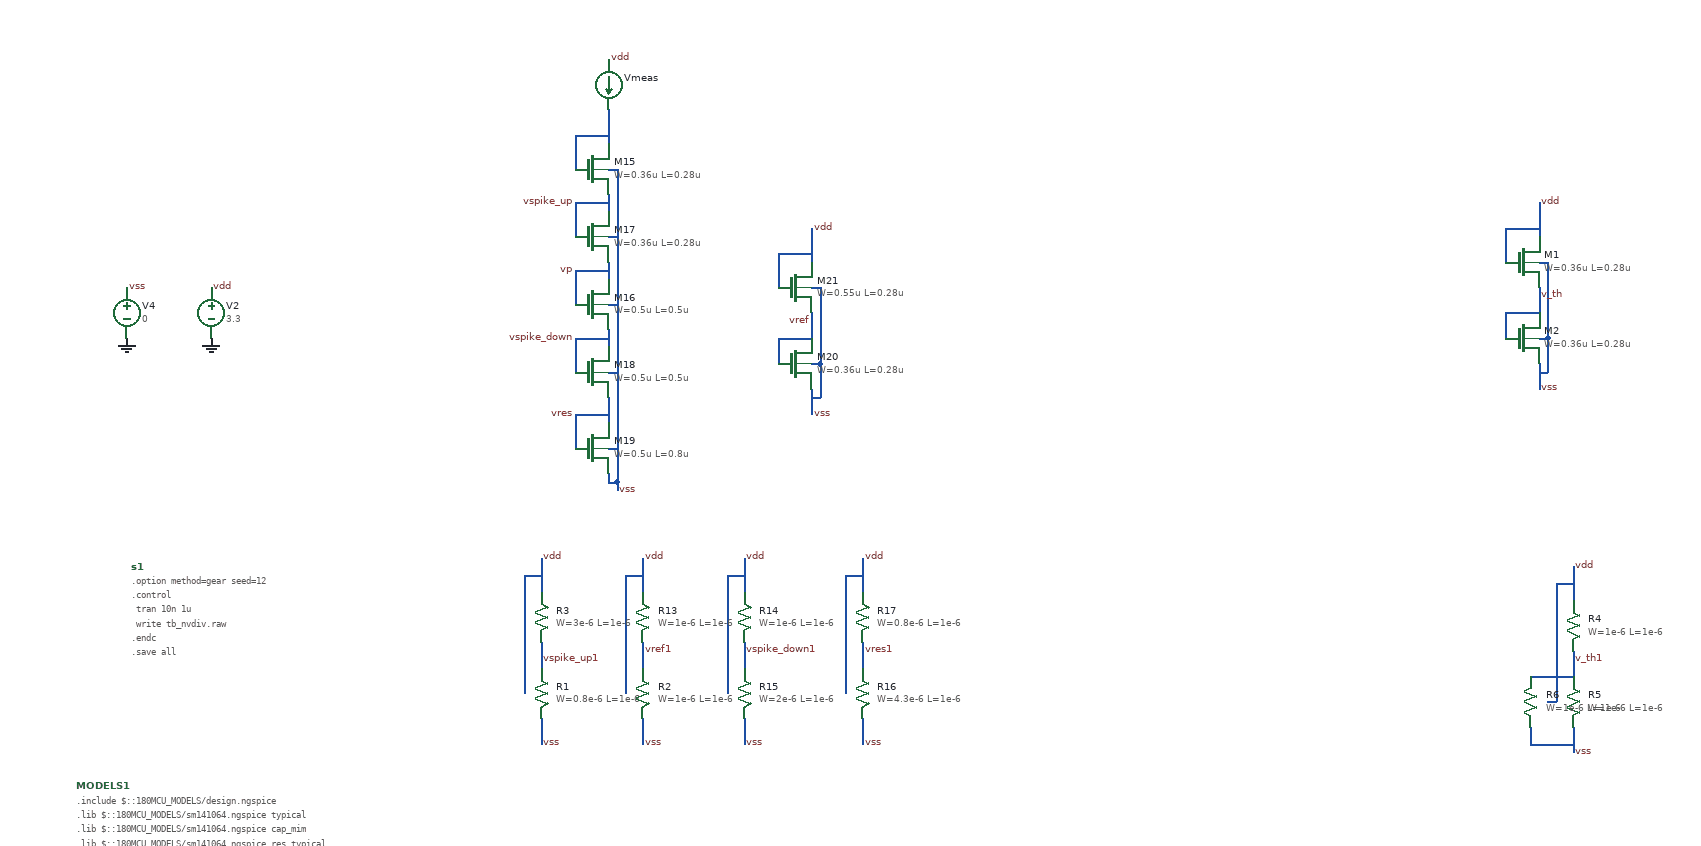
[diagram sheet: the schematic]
v {xschem version=3.4.7 file_version=1.2}
G {}
K {}
V {}
S {}
E {}
B 2 1110 -970 1580 -570 {flags=graph
y1=0
y2=3.3
ypos1=0
ypos2=2
divy=5
subdivy=1
unity=1
x1=0
x2=1e-06
divx=5
subdivx=1
xlabmag=1.0
ylabmag=1.0
dataset=-1
unitx=1
logx=0
logy=0
color="4 10 6 7"
node="vspike_up
vref
vspike_down
vres"}
B 2 1110 -570 1580 -170 {flags=graph
y1=0
y2=3.4
ypos1=0
ypos2=2
divy=5
subdivy=1
unity=1
x1=0
x2=1e-06
divx=5
subdivx=1
xlabmag=1.0
ylabmag=1.0
dataset=-1
unitx=1
logx=0
logy=0
color="4 10 6 7"
node="vspike_up1
vref1
vspike_down1
vres1"}
B 2 1910 -970 2380 -570 {flags=graph
y2=3.3
ypos1=0
ypos2=2
divy=5
subdivy=1
unity=1
x1=0
x2=1e-06
divx=5
subdivx=1
xlabmag=1.0
ylabmag=1.0
dataset=-1
unitx=1
logx=0
logy=0
color=4
node=v_th
y1=0}
B 2 1910 -570 2380 -170 {flags=graph
y1=0
y2=3.4
ypos1=0
ypos2=2
divy=5
subdivy=1
unity=1
x1=0
x2=1e-06
divx=5
subdivx=1
xlabmag=1.0
ylabmag=1.0
dataset=-1
unitx=1
logx=0
logy=0
color=4
node=v_th1}
N 630 -1000 630 -960 {lab=vdd}
N 590 -970 590 -930 {lab=vdd}
N 590 -970 630 -970 {lab=vdd}
N 630 -930 640 -930 {lab=vss}
N 640 -930 640 -640 {lab=vss}
N 630 -850 640 -850 {lab=vss}
N 630 -770 640 -770 {lab=vss}
N 630 -690 640 -690 {lab=vss}
N 630 -740 630 -720 {lab=vspike_down}
N 630 -820 630 -800 {lab=vp}
N 630 -900 630 -880 {lab=vspike_up}
N 590 -890 590 -850 {lab=vspike_up}
N 590 -890 630 -890 {lab=vspike_up}
N 590 -810 590 -770 {lab=vp}
N 590 -810 630 -810 {lab=vp}
N 590 -730 590 -690 {lab=vspike_down}
N 590 -730 630 -730 {lab=vspike_down}
N 630 -660 630 -650 {lab=vres}
N 630 -600 640 -600 {lab=vss}
N 630 -650 630 -630 {lab=vres}
N 590 -640 590 -600 {lab=vres}
N 590 -640 630 -640 {lab=vres}
N 630 -570 630 -560 {lab=vss}
N 640 -640 640 -560 {lab=vss}
N 640 -560 640 -550 {lab=vss}
N 630 -560 640 -560 {lab=vss}
N 870 -860 870 -820 {lab=vdd}
N 870 -760 870 -730 {lab=vref}
N 870 -670 870 -640 {lab=vss}
N 830 -830 830 -790 {lab=vdd}
N 830 -830 870 -830 {lab=vdd}
N 830 -730 830 -700 {lab=vref}
N 830 -730 870 -730 {lab=vref}
N 870 -790 880 -790 {lab=vss}
N 880 -790 880 -700 {lab=vss}
N 870 -700 880 -700 {lab=vss}
N 880 -700 880 -660 {lab=vss}
N 870 -660 880 -660 {lab=vss}
N 550 -470 550 -430 {lab=vdd}
N 530 -400 530 -310 {lab=vdd}
N 530 -450 530 -400 {lab=vdd}
N 530 -450 550 -450 {lab=vdd}
N 550 -370 550 -340 {lab=vspike_up1}
N 550 -280 550 -250 {lab=vss}
N 670 -470 670 -430 {lab=vdd}
N 650 -400 650 -310 {lab=vdd}
N 650 -450 650 -400 {lab=vdd}
N 650 -450 670 -450 {lab=vdd}
N 670 -370 670 -340 {lab=vref1}
N 670 -280 670 -250 {lab=vss}
N 790 -470 790 -430 {lab=vdd}
N 770 -400 770 -310 {lab=vdd}
N 770 -450 770 -400 {lab=vdd}
N 770 -450 790 -450 {lab=vdd}
N 790 -370 790 -340 {lab=vspike_down1}
N 790 -280 790 -250 {lab=vss}
N 930 -470 930 -430 {lab=vdd}
N 910 -400 910 -310 {lab=vdd}
N 910 -450 910 -400 {lab=vdd}
N 910 -450 930 -450 {lab=vdd}
N 930 -370 930 -340 {lab=vres1}
N 930 -280 930 -250 {lab=vss}
N 1770 -460 1770 -420 {lab=vdd}
N 1750 -390 1750 -300 {lab=vdd}
N 1750 -440 1750 -390 {lab=vdd}
N 1750 -440 1770 -440 {lab=vdd}
N 1770 -360 1770 -330 {lab=v_th1}
N 1770 -270 1770 -240 {lab=vss}
N 1720 -330 1770 -330 {lab=v_th1}
N 1720 -270 1720 -250 {lab=vss}
N 1740 -300 1750 -300 {lab=vdd}
N 1720 -250 1770 -250 {lab=vss}
N 1730 -890 1730 -850 {lab=vdd}
N 1730 -790 1730 -760 {lab=v_th}
N 1730 -700 1730 -670 {lab=vss}
N 1690 -860 1690 -820 {lab=vdd}
N 1690 -860 1730 -860 {lab=vdd}
N 1690 -760 1690 -730 {lab=v_th}
N 1690 -760 1730 -760 {lab=v_th}
N 1730 -820 1740 -820 {lab=vss}
N 1740 -820 1740 -730 {lab=vss}
N 1730 -730 1740 -730 {lab=vss}
N 1740 -730 1740 -690 {lab=vss}
N 1730 -690 1740 -690 {lab=vss}
C {title.sym} 160 0 0 0 {name=l1 author="Oscar Islas"}
C {vsource.sym} 160 -760 0 1 {name=V2 value=3.3 savecurrent=false}
C {gnd.sym} 160 -730 0 0 {name=l6 lab=GND}
C {lab_pin.sym} 160 -790 0 1 {name=p87 sig_type=std_logic lab=vdd}
C {devices/code_shown.sym} 65 -460 0 0 {name=s1 only_toplevel=false value="
.option method=gear seed=12
.control
    tran 10n 1u
    write tb_nvdiv.raw
.endc
.save all
"
spice_ignore=False}
C {devices/code_shown.sym} 0 -200 0 0 {name=MODELS1 only_toplevel=true
format="tcleval( @value )"
value="
.include $::180MCU_MODELS/design.ngspice
.lib $::180MCU_MODELS/sm141064.ngspice typical
.lib $::180MCU_MODELS/sm141064.ngspice cap_mim
.lib $::180MCU_MODELS/sm141064.ngspice res_typical
.lib $::180MCU_MODELS/sm141064.ngspice moscap_typical
.lib $::180MCU_MODELS/sm141064.ngspice mimcap_typical
"}
C {gnd.sym} 60 -730 0 0 {name=l3 lab=GND}
C {lab_pin.sym} 60 -790 0 1 {name=p1 sig_type=std_logic lab=vss}
C {vsource.sym} 60 -760 0 1 {name=V4 value=0 savecurrent=false}
C {launcher.sym} 860 -930 0 0 {name=h1
descr="load waves" 
tclcommand="xschem raw_read $netlist_dir/tb_nvdiv.raw tran"
}
C {lab_pin.sym} 630 -1060 0 1 {name=p9 sig_type=std_logic lab=vdd}
C {symbols/nfet_03v3.sym} 610 -930 0 0 {name=M15
L=0.28u
W=0.36u
nf=1
m=1
ad="'int((nf+1)/2) * W/nf * 0.18u'"
pd="'2*int((nf+1)/2) * (W/nf + 0.18u)'"
as="'int((nf+2)/2) * W/nf * 0.18u'"
ps="'2*int((nf+2)/2) * (W/nf + 0.18u)'"
nrd="'0.18u / W'" nrs="'0.18u / W'"
sa=0 sb=0 sd=0
model=nfet_03v3
spiceprefix=X
}
C {symbols/nfet_03v3.sym} 610 -690 0 0 {name=M18
L=0.5u
W=0.5u
nf=1
m=1
ad="'int((nf+1)/2) * W/nf * 0.18u'"
pd="'2*int((nf+1)/2) * (W/nf + 0.18u)'"
as="'int((nf+2)/2) * W/nf * 0.18u'"
ps="'2*int((nf+2)/2) * (W/nf + 0.18u)'"
nrd="'0.18u / W'" nrs="'0.18u / W'"
sa=0 sb=0 sd=0
model=nfet_03v3
spiceprefix=X
}
C {lab_pin.sym} 590 -890 0 0 {name=p11 sig_type=std_logic lab=vspike_up}
C {lab_pin.sym} 590 -810 0 0 {name=p12 sig_type=std_logic lab=vp}
C {lab_pin.sym} 590 -730 0 0 {name=p13 sig_type=std_logic lab=vspike_down}
C {lab_pin.sym} 640 -550 0 1 {name=p14 sig_type=std_logic lab=vss}
C {lab_pin.sym} 590 -640 0 0 {name=p15 sig_type=std_logic lab=vres}
C {lab_pin.sym} 870 -750 0 0 {name=p10 sig_type=std_logic lab=vref}
C {symbols/nfet_03v3.sym} 610 -770 0 0 {name=M16
L=0.5u
W=0.5u
nf=1
m=1
ad="'int((nf+1)/2) * W/nf * 0.18u'"
pd="'2*int((nf+1)/2) * (W/nf + 0.18u)'"
as="'int((nf+2)/2) * W/nf * 0.18u'"
ps="'2*int((nf+2)/2) * (W/nf + 0.18u)'"
nrd="'0.18u / W'" nrs="'0.18u / W'"
sa=0 sb=0 sd=0
model=nfet_03v3
spiceprefix=X
}
C {symbols/nfet_03v3.sym} 610 -600 0 0 {name=M19
L=0.8u
W=0.5u
nf=1
m=1
ad="'int((nf+1)/2) * W/nf * 0.18u'"
pd="'2*int((nf+1)/2) * (W/nf + 0.18u)'"
as="'int((nf+2)/2) * W/nf * 0.18u'"
ps="'2*int((nf+2)/2) * (W/nf + 0.18u)'"
nrd="'0.18u / W'" nrs="'0.18u / W'"
sa=0 sb=0 sd=0
model=nfet_03v3
spiceprefix=X
}
C {symbols/nfet_03v3.sym} 610 -850 0 0 {name=M17
L=0.28u
W=0.36u
nf=1
m=1
ad="'int((nf+1)/2) * W/nf * 0.18u'"
pd="'2*int((nf+1)/2) * (W/nf + 0.18u)'"
as="'int((nf+2)/2) * W/nf * 0.18u'"
ps="'2*int((nf+2)/2) * (W/nf + 0.18u)'"
nrd="'0.18u / W'" nrs="'0.18u / W'"
sa=0 sb=0 sd=0
model=nfet_03v3
spiceprefix=X
}
C {lab_pin.sym} 870 -860 0 1 {name=p16 sig_type=std_logic lab=vdd}
C {lab_pin.sym} 870 -640 0 1 {name=p17 sig_type=std_logic lab=vss}
C {symbols/nfet_03v3.sym} 850 -700 0 0 {name=M20
L=0.28u
W=0.36u
nf=1
m=1
ad="'int((nf+1)/2) * W/nf * 0.18u'"
pd="'2*int((nf+1)/2) * (W/nf + 0.18u)'"
as="'int((nf+2)/2) * W/nf * 0.18u'"
ps="'2*int((nf+2)/2) * (W/nf + 0.18u)'"
nrd="'0.18u / W'" nrs="'0.18u / W'"
sa=0 sb=0 sd=0
model=nfet_03v3
spiceprefix=X
}
C {symbols/nfet_03v3.sym} 850 -790 0 0 {name=M21
L=0.28u
W=0.55u
nf=1
m=1
ad="'int((nf+1)/2) * W/nf * 0.18u'"
pd="'2*int((nf+1)/2) * (W/nf + 0.18u)'"
as="'int((nf+2)/2) * W/nf * 0.18u'"
ps="'2*int((nf+2)/2) * (W/nf + 0.18u)'"
nrd="'0.18u / W'" nrs="'0.18u / W'"
sa=0 sb=0 sd=0
model=nfet_03v3
spiceprefix=X
}
C {lab_pin.sym} 550 -470 0 1 {name=p21 sig_type=std_logic lab=vdd}
C {lab_pin.sym} 550 -250 0 1 {name=p22 sig_type=std_logic lab=vss}
C {lab_pin.sym} 670 -470 0 1 {name=p31 sig_type=std_logic lab=vdd}
C {lab_pin.sym} 670 -250 0 1 {name=p32 sig_type=std_logic lab=vss}
C {lab_pin.sym} 670 -360 0 1 {name=p33 sig_type=std_logic lab=vref1}
C {lab_pin.sym} 790 -470 0 1 {name=p34 sig_type=std_logic lab=vdd}
C {lab_pin.sym} 790 -250 0 1 {name=p35 sig_type=std_logic lab=vss}
C {lab_pin.sym} 790 -360 0 1 {name=p36 sig_type=std_logic lab=vspike_down1}
C {lab_pin.sym} 930 -470 0 1 {name=p37 sig_type=std_logic lab=vdd}
C {lab_pin.sym} 930 -250 0 1 {name=p38 sig_type=std_logic lab=vss}
C {lab_pin.sym} 930 -360 0 1 {name=p39 sig_type=std_logic lab=vres1}
C {symbols/ppolyf_u.sym} 550 -400 0 0 {name=R3
W=3e-6
L=1e-6
model=ppolyf_u
spiceprefix=X
m=1}
C {symbols/ppolyf_u.sym} 550 -310 0 0 {name=R1
W=0.8e-6
L=1e-6
model=ppolyf_u
spiceprefix=X
m=1}
C {symbols/ppolyf_u.sym} 670 -310 0 0 {name=R2
W=1e-6
L=1e-6
model=ppolyf_u
spiceprefix=X
m=1}
C {symbols/ppolyf_u.sym} 670 -400 0 0 {name=R13
W=1e-6
L=1e-6
model=ppolyf_u
spiceprefix=X
m=1}
C {symbols/ppolyf_u.sym} 790 -400 0 0 {name=R14
W=1e-6
L=1e-6
model=ppolyf_u
spiceprefix=X
m=1}
C {symbols/ppolyf_u.sym} 790 -310 0 0 {name=R15
W=2e-6
L=1e-6
model=ppolyf_u
spiceprefix=X
m=1}
C {symbols/ppolyf_u.sym} 930 -310 0 0 {name=R16
W=4.3e-6
L=1e-6
model=ppolyf_u
spiceprefix=X
m=1}
C {symbols/ppolyf_u.sym} 930 -400 0 0 {name=R17
W=0.8e-6
L=1e-6
model=ppolyf_u
spiceprefix=X
m=1}
C {lab_pin.sym} 550 -350 0 1 {name=p40 sig_type=std_logic lab=vspike_up1}
C {symbols/ppolyf_u_3k.sym} 1770 -390 0 0 {name=R4
W=1e-6
L=1e-6
model=ppolyf_u_3k
spiceprefix=X
m=1}
C {symbols/ppolyf_u_1k.sym} 1770 -300 0 0 {name=R5
W=1e-6
L=1e-6
model=ppolyf_u_1k
spiceprefix=X
m=1}
C {lab_pin.sym} 1770 -460 0 1 {name=p2 sig_type=std_logic lab=vdd}
C {lab_pin.sym} 1770 -240 0 1 {name=p41 sig_type=std_logic lab=vss}
C {lab_pin.sym} 1770 -350 0 1 {name=p42 sig_type=std_logic lab=v_th1}
C {symbols/ppolyf_u_1k.sym} 1720 -300 0 1 {name=R6
W=1e-6
L=1e-6
model=ppolyf_u_1k
spiceprefix=X
m=1}
C {lab_pin.sym} 1730 -890 0 1 {name=p4 sig_type=std_logic lab=vdd}
C {lab_pin.sym} 1730 -670 0 1 {name=p5 sig_type=std_logic lab=vss}
C {symbols/nfet_03v3.sym} 1710 -820 0 0 {name=M1
L=0.28u
W=0.36u
nf=1
m=1
ad="'int((nf+1)/2) * W/nf * 0.18u'"
pd="'2*int((nf+1)/2) * (W/nf + 0.18u)'"
as="'int((nf+2)/2) * W/nf * 0.18u'"
ps="'2*int((nf+2)/2) * (W/nf + 0.18u)'"
nrd="'0.18u / W'" nrs="'0.18u / W'"
sa=0 sb=0 sd=0
model=nfet_03v3
spiceprefix=X
}
C {symbols/nfet_03v3.sym} 1710 -730 0 0 {name=M2
L=0.28u
W=0.36u
nf=1
m=5
ad="'int((nf+1)/2) * W/nf * 0.18u'"
pd="'2*int((nf+1)/2) * (W/nf + 0.18u)'"
as="'int((nf+2)/2) * W/nf * 0.18u'"
ps="'2*int((nf+2)/2) * (W/nf + 0.18u)'"
nrd="'0.18u / W'" nrs="'0.18u / W'"
sa=0 sb=0 sd=0
model=nfet_03v3
spiceprefix=X
}
C {lab_pin.sym} 1730 -780 0 1 {name=p3 sig_type=std_logic lab=v_th}
C {launcher.sym} 1719.375 -580 0 0 {name=h2
descr="load waves" 
tclcommand="xschem raw_read $netlist_dir/tb_nvdiv.raw tran"
}
C {ammeter.sym} 630 -1030 0 0 {name=Vmeas savecurrent=true spice_ignore=0}
